VERSION 5.7 ;
BUSBITCHARS "[]" ;
DIVIDERCHAR "/" ;

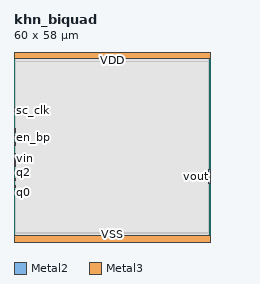
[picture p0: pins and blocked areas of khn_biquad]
MACRO khn_biquad
  CLASS BLOCK ;
  ORIGIN 0 0 ;
  FOREIGN khn_biquad 0 0 ;
  SIZE 60.000 BY 58.000 ;
  SYMMETRY X Y ;

  PIN vin
    DIRECTION INPUT ;
    USE SIGNAL ;
    PORT
      LAYER Metal2 ;
        RECT 0.000 23.000 0.500 27.000 ;
    END
  END vin

  PIN vout
    DIRECTION OUTPUT ;
    USE SIGNAL ;
    PORT
      LAYER Metal2 ;
        RECT 59.500 18.000 60.000 22.000 ;
    END
  END vout

  PIN en_lp
    DIRECTION INPUT ;
    USE SIGNAL ;
    PORT
      LAYER Metal2 ;
        RECT 0.000 29.500 0.500 30.500 ;
    END
  END en_lp

  PIN en_bp
    DIRECTION INPUT ;
    USE SIGNAL ;
    PORT
      LAYER Metal2 ;
        RECT 0.000 31.500 0.500 32.500 ;
    END
  END en_bp

  PIN en_hp
    DIRECTION INPUT ;
    USE SIGNAL ;
    PORT
      LAYER Metal2 ;
        RECT 0.000 33.500 0.500 34.500 ;
    END
  END en_hp

  PIN sc_clk
    DIRECTION INPUT ;
    USE SIGNAL ;
    PORT
      LAYER Metal2 ;
        RECT 0.000 39.000 0.500 41.000 ;
    END
  END sc_clk

  PIN q0
    DIRECTION INPUT ;
    USE SIGNAL ;
    PORT
      LAYER Metal2 ;
        RECT 0.000 14.700 0.500 15.300 ;
    END
  END q0

  PIN q1
    DIRECTION INPUT ;
    USE SIGNAL ;
    PORT
      LAYER Metal2 ;
        RECT 0.000 16.700 0.500 17.300 ;
    END
  END q1

  PIN q2
    DIRECTION INPUT ;
    USE SIGNAL ;
    PORT
      LAYER Metal2 ;
        RECT 0.000 18.700 0.500 19.300 ;
    END
  END q2

  PIN q3
    DIRECTION INPUT ;
    USE SIGNAL ;
    PORT
      LAYER Metal2 ;
        RECT 0.000 20.700 0.500 21.300 ;
    END
  END q3

  PIN VDD
    DIRECTION INOUT ;
    USE POWER ;
    PORT
      LAYER Metal3 ;
        RECT 0.000 56.000 60.000 58.000 ;
    END
  END VDD

  PIN VSS
    DIRECTION INOUT ;
    USE GROUND ;
    PORT
      LAYER Metal3 ;
        RECT 0.000 0.000 60.000 2.000 ;
    END
  END VSS

  OBS
    LAYER Metal1 ;
      RECT 0.500 0.500 59.500 57.500 ;
    LAYER Metal2 ;
      RECT 0.500 0.500 59.500 57.500 ;
    LAYER Metal3 ;
      RECT 0.500 2.000 59.500 56.000 ;
    LAYER Metal4 ;
      RECT 10.500 12.000 50.000 42.000 ;
    LAYER Metal5 ;
      RECT 0.500 2.500 59.500 37.000 ;
    LAYER TopMetal1 ;
      RECT 0.500 3.000 59.500 55.000 ;
  END

END khn_biquad

END LIBRARY
